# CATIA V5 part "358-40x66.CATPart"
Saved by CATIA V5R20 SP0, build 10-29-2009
Part number: 358-40X66
Definition: NONE
Nomenclature: 358-40X66
Source: Unknown
Description: 358-40X66
Bounding box of the stored display mesh (mm): x -18 to 48, y -26 to 26, z -26 to 26
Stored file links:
  C:\Users\Utente\Desktop\IO LAVORO\3D X SITO CF\X SITO\PLASTICA\358\358-40x66.CATPart

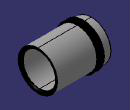
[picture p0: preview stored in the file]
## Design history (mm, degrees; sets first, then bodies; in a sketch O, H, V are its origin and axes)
Body1 "358-40X66" (main body)
  Solid1: solid without history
